VERSION 5.7 ;
  NOWIREEXTENSIONATPIN ON ;
  DIVIDERCHAR "/" ;
  BUSBITCHARS "[]" ;
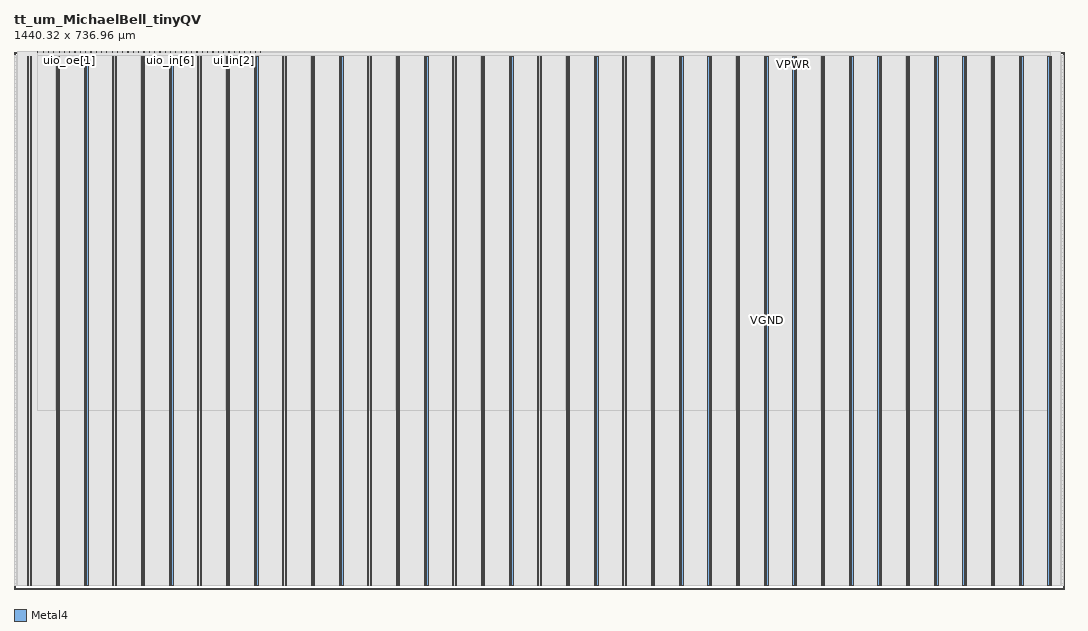
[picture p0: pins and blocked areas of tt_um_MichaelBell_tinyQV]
MACRO tt_um_MichaelBell_tinyQV
  CLASS BLOCK ;
  FOREIGN tt_um_MichaelBell_tinyQV ;
  ORIGIN 0.000 0.000 ;
  SIZE 1440.320 BY 736.960 ;
  PIN VGND
    DIRECTION INOUT ;
    USE GROUND ;
    PORT
      LAYER Metal4 ;
        RECT 22.180 4.740 23.780 731.100 ;
    END
    PORT
      LAYER Metal4 ;
        RECT 61.050 4.740 62.650 731.100 ;
    END
    PORT
      LAYER Metal4 ;
        RECT 99.920 4.740 101.520 731.100 ;
    END
    PORT
      LAYER Metal4 ;
        RECT 138.790 4.740 140.390 731.100 ;
    END
    PORT
      LAYER Metal4 ;
        RECT 177.660 4.740 179.260 731.100 ;
    END
    PORT
      LAYER Metal4 ;
        RECT 216.530 4.740 218.130 731.100 ;
    END
    PORT
      LAYER Metal4 ;
        RECT 255.400 4.740 257.000 731.100 ;
    END
    PORT
      LAYER Metal4 ;
        RECT 294.270 4.740 295.870 731.100 ;
    END
    PORT
      LAYER Metal4 ;
        RECT 333.140 4.740 334.740 731.100 ;
    END
    PORT
      LAYER Metal4 ;
        RECT 372.010 4.740 373.610 731.100 ;
    END
    PORT
      LAYER Metal4 ;
        RECT 410.880 4.740 412.480 731.100 ;
    END
    PORT
      LAYER Metal4 ;
        RECT 449.750 4.740 451.350 731.100 ;
    END
    PORT
      LAYER Metal4 ;
        RECT 488.620 4.740 490.220 731.100 ;
    END
    PORT
      LAYER Metal4 ;
        RECT 527.490 4.740 529.090 731.100 ;
    END
    PORT
      LAYER Metal4 ;
        RECT 566.360 4.740 567.960 731.100 ;
    END
    PORT
      LAYER Metal4 ;
        RECT 605.230 4.740 606.830 731.100 ;
    END
    PORT
      LAYER Metal4 ;
        RECT 644.100 4.740 645.700 731.100 ;
    END
    PORT
      LAYER Metal4 ;
        RECT 682.970 4.740 684.570 731.100 ;
    END
    PORT
      LAYER Metal4 ;
        RECT 721.840 4.740 723.440 731.100 ;
    END
    PORT
      LAYER Metal4 ;
        RECT 760.710 4.740 762.310 731.100 ;
    END
    PORT
      LAYER Metal4 ;
        RECT 799.580 4.740 801.180 731.100 ;
    END
    PORT
      LAYER Metal4 ;
        RECT 838.450 4.740 840.050 731.100 ;
    END
    PORT
      LAYER Metal4 ;
        RECT 877.320 4.740 878.920 731.100 ;
    END
    PORT
      LAYER Metal4 ;
        RECT 916.190 4.740 917.790 731.100 ;
    END
    PORT
      LAYER Metal4 ;
        RECT 955.060 4.740 956.660 731.100 ;
    END
    PORT
      LAYER Metal4 ;
        RECT 993.930 4.740 995.530 731.100 ;
    END
    PORT
      LAYER Metal4 ;
        RECT 1032.800 4.740 1034.400 731.100 ;
    END
    PORT
      LAYER Metal4 ;
        RECT 1071.670 4.740 1073.270 731.100 ;
    END
    PORT
      LAYER Metal4 ;
        RECT 1110.540 4.740 1112.140 731.100 ;
    END
    PORT
      LAYER Metal4 ;
        RECT 1149.410 4.740 1151.010 731.100 ;
    END
    PORT
      LAYER Metal4 ;
        RECT 1188.280 4.740 1189.880 731.100 ;
    END
    PORT
      LAYER Metal4 ;
        RECT 1227.150 4.740 1228.750 731.100 ;
    END
    PORT
      LAYER Metal4 ;
        RECT 1266.020 4.740 1267.620 731.100 ;
    END
    PORT
      LAYER Metal4 ;
        RECT 1304.890 4.740 1306.490 731.100 ;
    END
    PORT
      LAYER Metal4 ;
        RECT 1343.760 4.740 1345.360 731.100 ;
    END
    PORT
      LAYER Metal4 ;
        RECT 1382.630 4.740 1384.230 731.100 ;
    END
    PORT
      LAYER Metal4 ;
        RECT 1421.500 4.740 1423.100 731.100 ;
    END
  END VGND
  PIN VPWR
    DIRECTION INOUT ;
    USE POWER ;
    PORT
      LAYER Metal4 ;
        RECT 18.880 4.740 20.480 731.100 ;
    END
    PORT
      LAYER Metal4 ;
        RECT 57.750 4.740 59.350 731.100 ;
    END
    PORT
      LAYER Metal4 ;
        RECT 96.620 4.740 98.220 731.100 ;
    END
    PORT
      LAYER Metal4 ;
        RECT 135.490 4.740 137.090 731.100 ;
    END
    PORT
      LAYER Metal4 ;
        RECT 174.360 4.740 175.960 731.100 ;
    END
    PORT
      LAYER Metal4 ;
        RECT 213.230 4.740 214.830 731.100 ;
    END
    PORT
      LAYER Metal4 ;
        RECT 252.100 4.740 253.700 731.100 ;
    END
    PORT
      LAYER Metal4 ;
        RECT 290.970 4.740 292.570 731.100 ;
    END
    PORT
      LAYER Metal4 ;
        RECT 329.840 4.740 331.440 731.100 ;
    END
    PORT
      LAYER Metal4 ;
        RECT 368.710 4.740 370.310 731.100 ;
    END
    PORT
      LAYER Metal4 ;
        RECT 407.580 4.740 409.180 731.100 ;
    END
    PORT
      LAYER Metal4 ;
        RECT 446.450 4.740 448.050 731.100 ;
    END
    PORT
      LAYER Metal4 ;
        RECT 485.320 4.740 486.920 731.100 ;
    END
    PORT
      LAYER Metal4 ;
        RECT 524.190 4.740 525.790 731.100 ;
    END
    PORT
      LAYER Metal4 ;
        RECT 563.060 4.740 564.660 731.100 ;
    END
    PORT
      LAYER Metal4 ;
        RECT 601.930 4.740 603.530 731.100 ;
    END
    PORT
      LAYER Metal4 ;
        RECT 640.800 4.740 642.400 731.100 ;
    END
    PORT
      LAYER Metal4 ;
        RECT 679.670 4.740 681.270 731.100 ;
    END
    PORT
      LAYER Metal4 ;
        RECT 718.540 4.740 720.140 731.100 ;
    END
    PORT
      LAYER Metal4 ;
        RECT 757.410 4.740 759.010 731.100 ;
    END
    PORT
      LAYER Metal4 ;
        RECT 796.280 4.740 797.880 731.100 ;
    END
    PORT
      LAYER Metal4 ;
        RECT 835.150 4.740 836.750 731.100 ;
    END
    PORT
      LAYER Metal4 ;
        RECT 874.020 4.740 875.620 731.100 ;
    END
    PORT
      LAYER Metal4 ;
        RECT 912.890 4.740 914.490 731.100 ;
    END
    PORT
      LAYER Metal4 ;
        RECT 951.760 4.740 953.360 731.100 ;
    END
    PORT
      LAYER Metal4 ;
        RECT 990.630 4.740 992.230 731.100 ;
    END
    PORT
      LAYER Metal4 ;
        RECT 1029.500 4.740 1031.100 731.100 ;
    END
    PORT
      LAYER Metal4 ;
        RECT 1068.370 4.740 1069.970 731.100 ;
    END
    PORT
      LAYER Metal4 ;
        RECT 1107.240 4.740 1108.840 731.100 ;
    END
    PORT
      LAYER Metal4 ;
        RECT 1146.110 4.740 1147.710 731.100 ;
    END
    PORT
      LAYER Metal4 ;
        RECT 1184.980 4.740 1186.580 731.100 ;
    END
    PORT
      LAYER Metal4 ;
        RECT 1223.850 4.740 1225.450 731.100 ;
    END
    PORT
      LAYER Metal4 ;
        RECT 1262.720 4.740 1264.320 731.100 ;
    END
    PORT
      LAYER Metal4 ;
        RECT 1301.590 4.740 1303.190 731.100 ;
    END
    PORT
      LAYER Metal4 ;
        RECT 1340.460 4.740 1342.060 731.100 ;
    END
    PORT
      LAYER Metal4 ;
        RECT 1379.330 4.740 1380.930 731.100 ;
    END
    PORT
      LAYER Metal4 ;
        RECT 1418.200 4.740 1419.800 731.100 ;
    END
  END VPWR
  PIN clk
    DIRECTION INPUT ;
    USE SIGNAL ;
    ANTENNAGATEAREA 10.823999 ;
    PORT
      LAYER Metal4 ;
        RECT 331.090 735.960 331.390 736.960 ;
    END
  END clk
  PIN ena
    DIRECTION INPUT ;
    USE SIGNAL ;
    PORT
      LAYER Metal4 ;
        RECT 338.370 735.960 338.670 736.960 ;
    END
  END ena
  PIN rst_n
    DIRECTION INPUT ;
    USE SIGNAL ;
    ANTENNAGATEAREA 0.396000 ;
    PORT
      LAYER Metal4 ;
        RECT 323.810 735.960 324.110 736.960 ;
    END
  END rst_n
  PIN ui_in[0]
    DIRECTION INPUT ;
    USE SIGNAL ;
    ANTENNAGATEAREA 0.396000 ;
    PORT
      LAYER Metal4 ;
        RECT 316.530 735.960 316.830 736.960 ;
    END
  END ui_in[0]
  PIN ui_in[1]
    DIRECTION INPUT ;
    USE SIGNAL ;
    ANTENNAGATEAREA 0.396000 ;
    PORT
      LAYER Metal4 ;
        RECT 309.250 735.960 309.550 736.960 ;
    END
  END ui_in[1]
  PIN ui_in[2]
    DIRECTION INPUT ;
    USE SIGNAL ;
    ANTENNAGATEAREA 0.396000 ;
    PORT
      LAYER Metal4 ;
        RECT 301.970 735.960 302.270 736.960 ;
    END
  END ui_in[2]
  PIN ui_in[3]
    DIRECTION INPUT ;
    USE SIGNAL ;
    ANTENNAGATEAREA 0.396000 ;
    PORT
      LAYER Metal4 ;
        RECT 294.690 735.960 294.990 736.960 ;
    END
  END ui_in[3]
  PIN ui_in[4]
    DIRECTION INPUT ;
    USE SIGNAL ;
    ANTENNAGATEAREA 0.396000 ;
    PORT
      LAYER Metal4 ;
        RECT 287.410 735.960 287.710 736.960 ;
    END
  END ui_in[4]
  PIN ui_in[5]
    DIRECTION INPUT ;
    USE SIGNAL ;
    ANTENNAGATEAREA 0.396000 ;
    PORT
      LAYER Metal4 ;
        RECT 280.130 735.960 280.430 736.960 ;
    END
  END ui_in[5]
  PIN ui_in[6]
    DIRECTION INPUT ;
    USE SIGNAL ;
    ANTENNAGATEAREA 0.396000 ;
    PORT
      LAYER Metal4 ;
        RECT 272.850 735.960 273.150 736.960 ;
    END
  END ui_in[6]
  PIN ui_in[7]
    DIRECTION INPUT ;
    USE SIGNAL ;
    ANTENNAGATEAREA 0.396000 ;
    PORT
      LAYER Metal4 ;
        RECT 265.570 735.960 265.870 736.960 ;
    END
  END ui_in[7]
  PIN uio_in[0]
    DIRECTION INPUT ;
    USE SIGNAL ;
    PORT
      LAYER Metal4 ;
        RECT 258.290 735.960 258.590 736.960 ;
    END
  END uio_in[0]
  PIN uio_in[1]
    DIRECTION INPUT ;
    USE SIGNAL ;
    ANTENNAGATEAREA 0.396000 ;
    PORT
      LAYER Metal4 ;
        RECT 251.010 735.960 251.310 736.960 ;
    END
  END uio_in[1]
  PIN uio_in[2]
    DIRECTION INPUT ;
    USE SIGNAL ;
    ANTENNAGATEAREA 0.396000 ;
    PORT
      LAYER Metal4 ;
        RECT 243.730 735.960 244.030 736.960 ;
    END
  END uio_in[2]
  PIN uio_in[3]
    DIRECTION INPUT ;
    USE SIGNAL ;
    PORT
      LAYER Metal4 ;
        RECT 236.450 735.960 236.750 736.960 ;
    END
  END uio_in[3]
  PIN uio_in[4]
    DIRECTION INPUT ;
    USE SIGNAL ;
    ANTENNAGATEAREA 0.396000 ;
    PORT
      LAYER Metal4 ;
        RECT 229.170 735.960 229.470 736.960 ;
    END
  END uio_in[4]
  PIN uio_in[5]
    DIRECTION INPUT ;
    USE SIGNAL ;
    ANTENNAGATEAREA 0.396000 ;
    PORT
      LAYER Metal4 ;
        RECT 221.890 735.960 222.190 736.960 ;
    END
  END uio_in[5]
  PIN uio_in[6]
    DIRECTION INPUT ;
    USE SIGNAL ;
    PORT
      LAYER Metal4 ;
        RECT 214.610 735.960 214.910 736.960 ;
    END
  END uio_in[6]
  PIN uio_in[7]
    DIRECTION INPUT ;
    USE SIGNAL ;
    PORT
      LAYER Metal4 ;
        RECT 207.330 735.960 207.630 736.960 ;
    END
  END uio_in[7]
  PIN uio_oe[0]
    DIRECTION OUTPUT ;
    USE SIGNAL ;
    ANTENNADIFFAREA 1.386000 ;
    PORT
      LAYER Metal4 ;
        RECT 83.570 735.960 83.870 736.960 ;
    END
  END uio_oe[0]
  PIN uio_oe[1]
    DIRECTION OUTPUT ;
    USE SIGNAL ;
    ANTENNADIFFAREA 1.386000 ;
    PORT
      LAYER Metal4 ;
        RECT 76.290 735.960 76.590 736.960 ;
    END
  END uio_oe[1]
  PIN uio_oe[2]
    DIRECTION OUTPUT ;
    USE SIGNAL ;
    ANTENNADIFFAREA 1.386000 ;
    PORT
      LAYER Metal4 ;
        RECT 69.010 735.960 69.310 736.960 ;
    END
  END uio_oe[2]
  PIN uio_oe[3]
    DIRECTION OUTPUT ;
    USE SIGNAL ;
    ANTENNADIFFAREA 1.386000 ;
    PORT
      LAYER Metal4 ;
        RECT 61.730 735.960 62.030 736.960 ;
    END
  END uio_oe[3]
  PIN uio_oe[4]
    DIRECTION OUTPUT ;
    USE SIGNAL ;
    ANTENNADIFFAREA 1.386000 ;
    PORT
      LAYER Metal4 ;
        RECT 54.450 735.960 54.750 736.960 ;
    END
  END uio_oe[4]
  PIN uio_oe[5]
    DIRECTION OUTPUT ;
    USE SIGNAL ;
    ANTENNAGATEAREA 1.707000 ;
    ANTENNADIFFAREA 1.386000 ;
    PORT
      LAYER Metal4 ;
        RECT 47.170 735.960 47.470 736.960 ;
    END
  END uio_oe[5]
  PIN uio_oe[6]
    DIRECTION OUTPUT ;
    USE SIGNAL ;
    ANTENNADIFFAREA 1.386000 ;
    PORT
      LAYER Metal4 ;
        RECT 39.890 735.960 40.190 736.960 ;
    END
  END uio_oe[6]
  PIN uio_oe[7]
    DIRECTION OUTPUT ;
    USE SIGNAL ;
    ANTENNADIFFAREA 1.386000 ;
    PORT
      LAYER Metal4 ;
        RECT 32.610 735.960 32.910 736.960 ;
    END
  END uio_oe[7]
  PIN uio_out[0]
    DIRECTION OUTPUT ;
    USE SIGNAL ;
    ANTENNADIFFAREA 1.386000 ;
    PORT
      LAYER Metal4 ;
        RECT 141.810 735.960 142.110 736.960 ;
    END
  END uio_out[0]
  PIN uio_out[1]
    DIRECTION OUTPUT ;
    USE SIGNAL ;
    ANTENNADIFFAREA 1.126400 ;
    PORT
      LAYER Metal4 ;
        RECT 134.530 735.960 134.830 736.960 ;
    END
  END uio_out[1]
  PIN uio_out[2]
    DIRECTION OUTPUT ;
    USE SIGNAL ;
    ANTENNADIFFAREA 1.126400 ;
    PORT
      LAYER Metal4 ;
        RECT 127.250 735.960 127.550 736.960 ;
    END
  END uio_out[2]
  PIN uio_out[3]
    DIRECTION OUTPUT ;
    USE SIGNAL ;
    ANTENNADIFFAREA 1.386000 ;
    PORT
      LAYER Metal4 ;
        RECT 119.970 735.960 120.270 736.960 ;
    END
  END uio_out[3]
  PIN uio_out[4]
    DIRECTION OUTPUT ;
    USE SIGNAL ;
    ANTENNADIFFAREA 3.287600 ;
    PORT
      LAYER Metal4 ;
        RECT 112.690 735.960 112.990 736.960 ;
    END
  END uio_out[4]
  PIN uio_out[5]
    DIRECTION OUTPUT ;
    USE SIGNAL ;
    ANTENNADIFFAREA 1.126400 ;
    PORT
      LAYER Metal4 ;
        RECT 105.410 735.960 105.710 736.960 ;
    END
  END uio_out[5]
  PIN uio_out[6]
    DIRECTION OUTPUT ;
    USE SIGNAL ;
    ANTENNADIFFAREA 1.386000 ;
    PORT
      LAYER Metal4 ;
        RECT 98.130 735.960 98.430 736.960 ;
    END
  END uio_out[6]
  PIN uio_out[7]
    DIRECTION OUTPUT ;
    USE SIGNAL ;
    ANTENNADIFFAREA 1.386000 ;
    PORT
      LAYER Metal4 ;
        RECT 90.850 735.960 91.150 736.960 ;
    END
  END uio_out[7]
  PIN uo_out[0]
    DIRECTION OUTPUT ;
    USE SIGNAL ;
    ANTENNADIFFAREA 3.733500 ;
    PORT
      LAYER Metal4 ;
        RECT 200.050 735.960 200.350 736.960 ;
    END
  END uo_out[0]
  PIN uo_out[1]
    DIRECTION OUTPUT ;
    USE SIGNAL ;
    ANTENNADIFFAREA 3.362800 ;
    PORT
      LAYER Metal4 ;
        RECT 192.770 735.960 193.070 736.960 ;
    END
  END uo_out[1]
  PIN uo_out[2]
    DIRECTION OUTPUT ;
    USE SIGNAL ;
    ANTENNADIFFAREA 1.386000 ;
    PORT
      LAYER Metal4 ;
        RECT 185.490 735.960 185.790 736.960 ;
    END
  END uo_out[2]
  PIN uo_out[3]
    DIRECTION OUTPUT ;
    USE SIGNAL ;
    ANTENNADIFFAREA 1.386000 ;
    PORT
      LAYER Metal4 ;
        RECT 178.210 735.960 178.510 736.960 ;
    END
  END uo_out[3]
  PIN uo_out[4]
    DIRECTION OUTPUT ;
    USE SIGNAL ;
    ANTENNADIFFAREA 1.386000 ;
    PORT
      LAYER Metal4 ;
        RECT 170.930 735.960 171.230 736.960 ;
    END
  END uo_out[4]
  PIN uo_out[5]
    DIRECTION OUTPUT ;
    USE SIGNAL ;
    ANTENNADIFFAREA 1.386000 ;
    PORT
      LAYER Metal4 ;
        RECT 163.650 735.960 163.950 736.960 ;
    END
  END uo_out[5]
  PIN uo_out[6]
    DIRECTION OUTPUT ;
    USE SIGNAL ;
    ANTENNADIFFAREA 1.915500 ;
    PORT
      LAYER Metal4 ;
        RECT 156.370 735.960 156.670 736.960 ;
    END
  END uo_out[6]
  PIN uo_out[7]
    DIRECTION OUTPUT ;
    USE SIGNAL ;
    ANTENNADIFFAREA 3.362800 ;
    PORT
      LAYER Metal4 ;
        RECT 149.090 735.960 149.390 736.960 ;
    END
  END uo_out[7]
  OBS
      LAYER Pwell ;
        RECT 0.430 728.535 1439.890 731.230 ;
      LAYER Nwell ;
        RECT 0.430 722.985 1439.890 728.535 ;
      LAYER Pwell ;
        RECT 0.430 718.455 1439.890 722.985 ;
      LAYER Nwell ;
        RECT 0.430 712.905 1439.890 718.455 ;
      LAYER Pwell ;
        RECT 0.430 708.375 1439.890 712.905 ;
      LAYER Nwell ;
        RECT 0.430 702.825 1439.890 708.375 ;
      LAYER Pwell ;
        RECT 0.430 698.295 1439.890 702.825 ;
      LAYER Nwell ;
        RECT 0.430 692.745 1439.890 698.295 ;
      LAYER Pwell ;
        RECT 0.430 688.215 1439.890 692.745 ;
      LAYER Nwell ;
        RECT 0.430 682.665 1439.890 688.215 ;
      LAYER Pwell ;
        RECT 0.430 678.135 1439.890 682.665 ;
      LAYER Nwell ;
        RECT 0.430 672.585 1439.890 678.135 ;
      LAYER Pwell ;
        RECT 0.430 668.055 1439.890 672.585 ;
      LAYER Nwell ;
        RECT 0.430 662.505 1439.890 668.055 ;
      LAYER Pwell ;
        RECT 0.430 657.975 1439.890 662.505 ;
      LAYER Nwell ;
        RECT 0.430 652.425 1439.890 657.975 ;
      LAYER Pwell ;
        RECT 0.430 647.895 1439.890 652.425 ;
      LAYER Nwell ;
        RECT 0.430 642.345 1439.890 647.895 ;
      LAYER Pwell ;
        RECT 0.430 637.815 1439.890 642.345 ;
      LAYER Nwell ;
        RECT 0.430 632.265 1439.890 637.815 ;
      LAYER Pwell ;
        RECT 0.430 627.735 1439.890 632.265 ;
      LAYER Nwell ;
        RECT 0.430 622.185 1439.890 627.735 ;
      LAYER Pwell ;
        RECT 0.430 617.655 1439.890 622.185 ;
      LAYER Nwell ;
        RECT 0.430 612.105 1439.890 617.655 ;
      LAYER Pwell ;
        RECT 0.430 607.575 1439.890 612.105 ;
      LAYER Nwell ;
        RECT 0.430 602.025 1439.890 607.575 ;
      LAYER Pwell ;
        RECT 0.430 597.495 1439.890 602.025 ;
      LAYER Nwell ;
        RECT 0.430 591.945 1439.890 597.495 ;
      LAYER Pwell ;
        RECT 0.430 587.415 1439.890 591.945 ;
      LAYER Nwell ;
        RECT 0.430 581.865 1439.890 587.415 ;
      LAYER Pwell ;
        RECT 0.430 577.335 1439.890 581.865 ;
      LAYER Nwell ;
        RECT 0.430 571.785 1439.890 577.335 ;
      LAYER Pwell ;
        RECT 0.430 567.255 1439.890 571.785 ;
      LAYER Nwell ;
        RECT 0.430 561.705 1439.890 567.255 ;
      LAYER Pwell ;
        RECT 0.430 557.175 1439.890 561.705 ;
      LAYER Nwell ;
        RECT 0.430 551.625 1439.890 557.175 ;
      LAYER Pwell ;
        RECT 0.430 547.095 1439.890 551.625 ;
      LAYER Nwell ;
        RECT 0.430 541.545 1439.890 547.095 ;
      LAYER Pwell ;
        RECT 0.430 537.015 1439.890 541.545 ;
      LAYER Nwell ;
        RECT 0.430 531.465 1439.890 537.015 ;
      LAYER Pwell ;
        RECT 0.430 526.935 1439.890 531.465 ;
      LAYER Nwell ;
        RECT 0.430 521.385 1439.890 526.935 ;
      LAYER Pwell ;
        RECT 0.430 516.855 1439.890 521.385 ;
      LAYER Nwell ;
        RECT 0.430 511.305 1439.890 516.855 ;
      LAYER Pwell ;
        RECT 0.430 506.775 1439.890 511.305 ;
      LAYER Nwell ;
        RECT 0.430 501.225 1439.890 506.775 ;
      LAYER Pwell ;
        RECT 0.430 496.695 1439.890 501.225 ;
      LAYER Nwell ;
        RECT 0.430 491.145 1439.890 496.695 ;
      LAYER Pwell ;
        RECT 0.430 486.615 1439.890 491.145 ;
      LAYER Nwell ;
        RECT 0.430 481.065 1439.890 486.615 ;
      LAYER Pwell ;
        RECT 0.430 476.535 1439.890 481.065 ;
      LAYER Nwell ;
        RECT 0.430 470.985 1439.890 476.535 ;
      LAYER Pwell ;
        RECT 0.430 466.455 1439.890 470.985 ;
      LAYER Nwell ;
        RECT 0.430 460.905 1439.890 466.455 ;
      LAYER Pwell ;
        RECT 0.430 456.375 1439.890 460.905 ;
      LAYER Nwell ;
        RECT 0.430 450.825 1439.890 456.375 ;
      LAYER Pwell ;
        RECT 0.430 446.295 1439.890 450.825 ;
      LAYER Nwell ;
        RECT 0.430 440.745 1439.890 446.295 ;
      LAYER Pwell ;
        RECT 0.430 436.215 1439.890 440.745 ;
      LAYER Nwell ;
        RECT 0.430 430.665 1439.890 436.215 ;
      LAYER Pwell ;
        RECT 0.430 426.135 1439.890 430.665 ;
      LAYER Nwell ;
        RECT 0.430 420.585 1439.890 426.135 ;
      LAYER Pwell ;
        RECT 0.430 416.055 1439.890 420.585 ;
      LAYER Nwell ;
        RECT 0.430 410.505 1439.890 416.055 ;
      LAYER Pwell ;
        RECT 0.430 405.975 1439.890 410.505 ;
      LAYER Nwell ;
        RECT 0.430 400.425 1439.890 405.975 ;
      LAYER Pwell ;
        RECT 0.430 395.895 1439.890 400.425 ;
      LAYER Nwell ;
        RECT 0.430 390.345 1439.890 395.895 ;
      LAYER Pwell ;
        RECT 0.430 385.815 1439.890 390.345 ;
      LAYER Nwell ;
        RECT 0.430 380.265 1439.890 385.815 ;
      LAYER Pwell ;
        RECT 0.430 375.735 1439.890 380.265 ;
      LAYER Nwell ;
        RECT 0.430 370.185 1439.890 375.735 ;
      LAYER Pwell ;
        RECT 0.430 365.655 1439.890 370.185 ;
      LAYER Nwell ;
        RECT 0.430 360.105 1439.890 365.655 ;
      LAYER Pwell ;
        RECT 0.430 355.575 1439.890 360.105 ;
      LAYER Nwell ;
        RECT 0.430 350.025 1439.890 355.575 ;
      LAYER Pwell ;
        RECT 0.430 345.495 1439.890 350.025 ;
      LAYER Nwell ;
        RECT 0.430 339.945 1439.890 345.495 ;
      LAYER Pwell ;
        RECT 0.430 335.415 1439.890 339.945 ;
      LAYER Nwell ;
        RECT 0.430 329.865 1439.890 335.415 ;
      LAYER Pwell ;
        RECT 0.430 325.335 1439.890 329.865 ;
      LAYER Nwell ;
        RECT 0.430 319.785 1439.890 325.335 ;
      LAYER Pwell ;
        RECT 0.430 315.255 1439.890 319.785 ;
      LAYER Nwell ;
        RECT 0.430 309.705 1439.890 315.255 ;
      LAYER Pwell ;
        RECT 0.430 305.175 1439.890 309.705 ;
      LAYER Nwell ;
        RECT 0.430 299.625 1439.890 305.175 ;
      LAYER Pwell ;
        RECT 0.430 295.095 1439.890 299.625 ;
      LAYER Nwell ;
        RECT 0.430 289.545 1439.890 295.095 ;
      LAYER Pwell ;
        RECT 0.430 285.015 1439.890 289.545 ;
      LAYER Nwell ;
        RECT 0.430 279.465 1439.890 285.015 ;
      LAYER Pwell ;
        RECT 0.430 274.935 1439.890 279.465 ;
      LAYER Nwell ;
        RECT 0.430 269.385 1439.890 274.935 ;
      LAYER Pwell ;
        RECT 0.430 264.855 1439.890 269.385 ;
      LAYER Nwell ;
        RECT 0.430 259.305 1439.890 264.855 ;
      LAYER Pwell ;
        RECT 0.430 254.775 1439.890 259.305 ;
      LAYER Nwell ;
        RECT 0.430 249.225 1439.890 254.775 ;
      LAYER Pwell ;
        RECT 0.430 244.695 1439.890 249.225 ;
      LAYER Nwell ;
        RECT 0.430 239.145 1439.890 244.695 ;
      LAYER Pwell ;
        RECT 0.430 234.615 1439.890 239.145 ;
      LAYER Nwell ;
        RECT 0.430 229.065 1439.890 234.615 ;
      LAYER Pwell ;
        RECT 0.430 224.535 1439.890 229.065 ;
      LAYER Nwell ;
        RECT 0.430 218.985 1439.890 224.535 ;
      LAYER Pwell ;
        RECT 0.430 214.455 1439.890 218.985 ;
      LAYER Nwell ;
        RECT 0.430 208.905 1439.890 214.455 ;
      LAYER Pwell ;
        RECT 0.430 204.375 1439.890 208.905 ;
      LAYER Nwell ;
        RECT 0.430 198.825 1439.890 204.375 ;
      LAYER Pwell ;
        RECT 0.430 194.295 1439.890 198.825 ;
      LAYER Nwell ;
        RECT 0.430 188.745 1439.890 194.295 ;
      LAYER Pwell ;
        RECT 0.430 184.215 1439.890 188.745 ;
      LAYER Nwell ;
        RECT 0.430 178.665 1439.890 184.215 ;
      LAYER Pwell ;
        RECT 0.430 174.135 1439.890 178.665 ;
      LAYER Nwell ;
        RECT 0.430 168.585 1439.890 174.135 ;
      LAYER Pwell ;
        RECT 0.430 164.055 1439.890 168.585 ;
      LAYER Nwell ;
        RECT 0.430 158.505 1439.890 164.055 ;
      LAYER Pwell ;
        RECT 0.430 153.975 1439.890 158.505 ;
      LAYER Nwell ;
        RECT 0.430 148.425 1439.890 153.975 ;
      LAYER Pwell ;
        RECT 0.430 143.895 1439.890 148.425 ;
      LAYER Nwell ;
        RECT 0.430 138.345 1439.890 143.895 ;
      LAYER Pwell ;
        RECT 0.430 133.815 1439.890 138.345 ;
      LAYER Nwell ;
        RECT 0.430 128.265 1439.890 133.815 ;
      LAYER Pwell ;
        RECT 0.430 123.735 1439.890 128.265 ;
      LAYER Nwell ;
        RECT 0.430 118.185 1439.890 123.735 ;
      LAYER Pwell ;
        RECT 0.430 113.655 1439.890 118.185 ;
      LAYER Nwell ;
        RECT 0.430 108.105 1439.890 113.655 ;
      LAYER Pwell ;
        RECT 0.430 103.575 1439.890 108.105 ;
      LAYER Nwell ;
        RECT 0.430 98.025 1439.890 103.575 ;
      LAYER Pwell ;
        RECT 0.430 93.495 1439.890 98.025 ;
      LAYER Nwell ;
        RECT 0.430 87.945 1439.890 93.495 ;
      LAYER Pwell ;
        RECT 0.430 83.415 1439.890 87.945 ;
      LAYER Nwell ;
        RECT 0.430 77.865 1439.890 83.415 ;
      LAYER Pwell ;
        RECT 0.430 73.335 1439.890 77.865 ;
      LAYER Nwell ;
        RECT 0.430 67.785 1439.890 73.335 ;
      LAYER Pwell ;
        RECT 0.430 63.255 1439.890 67.785 ;
      LAYER Nwell ;
        RECT 0.430 57.705 1439.890 63.255 ;
      LAYER Pwell ;
        RECT 0.430 53.175 1439.890 57.705 ;
      LAYER Nwell ;
        RECT 0.430 47.625 1439.890 53.175 ;
      LAYER Pwell ;
        RECT 0.430 43.095 1439.890 47.625 ;
      LAYER Nwell ;
        RECT 0.430 37.545 1439.890 43.095 ;
      LAYER Pwell ;
        RECT 0.430 33.015 1439.890 37.545 ;
      LAYER Nwell ;
        RECT 0.430 27.465 1439.890 33.015 ;
      LAYER Pwell ;
        RECT 0.430 22.935 1439.890 27.465 ;
      LAYER Nwell ;
        RECT 0.430 17.385 1439.890 22.935 ;
      LAYER Pwell ;
        RECT 0.430 12.855 1439.890 17.385 ;
      LAYER Nwell ;
        RECT 0.430 7.305 1439.890 12.855 ;
      LAYER Pwell ;
        RECT 0.430 4.610 1439.890 7.305 ;
      LAYER Metal1 ;
        RECT 3.360 4.590 1436.960 731.250 ;
      LAYER Metal2 ;
        RECT 5.180 4.850 1435.140 736.870 ;
      LAYER Metal3 ;
        RECT 5.130 4.900 1435.190 736.820 ;
      LAYER Metal4 ;
        RECT 33.210 735.660 39.590 735.960 ;
        RECT 40.490 735.660 46.870 735.960 ;
        RECT 47.770 735.660 54.150 735.960 ;
        RECT 55.050 735.660 61.430 735.960 ;
        RECT 62.330 735.660 68.710 735.960 ;
        RECT 69.610 735.660 75.990 735.960 ;
        RECT 76.890 735.660 83.270 735.960 ;
        RECT 84.170 735.660 90.550 735.960 ;
        RECT 91.450 735.660 97.830 735.960 ;
        RECT 98.730 735.660 105.110 735.960 ;
        RECT 106.010 735.660 112.390 735.960 ;
        RECT 113.290 735.660 119.670 735.960 ;
        RECT 120.570 735.660 126.950 735.960 ;
        RECT 127.850 735.660 134.230 735.960 ;
        RECT 135.130 735.660 141.510 735.960 ;
        RECT 142.410 735.660 148.790 735.960 ;
        RECT 149.690 735.660 156.070 735.960 ;
        RECT 156.970 735.660 163.350 735.960 ;
        RECT 164.250 735.660 170.630 735.960 ;
        RECT 171.530 735.660 177.910 735.960 ;
        RECT 178.810 735.660 185.190 735.960 ;
        RECT 186.090 735.660 192.470 735.960 ;
        RECT 193.370 735.660 199.750 735.960 ;
        RECT 200.650 735.660 207.030 735.960 ;
        RECT 207.930 735.660 214.310 735.960 ;
        RECT 215.210 735.660 221.590 735.960 ;
        RECT 222.490 735.660 228.870 735.960 ;
        RECT 229.770 735.660 236.150 735.960 ;
        RECT 237.050 735.660 243.430 735.960 ;
        RECT 244.330 735.660 250.710 735.960 ;
        RECT 251.610 735.660 257.990 735.960 ;
        RECT 258.890 735.660 265.270 735.960 ;
        RECT 266.170 735.660 272.550 735.960 ;
        RECT 273.450 735.660 279.830 735.960 ;
        RECT 280.730 735.660 287.110 735.960 ;
        RECT 288.010 735.660 294.390 735.960 ;
        RECT 295.290 735.660 301.670 735.960 ;
        RECT 302.570 735.660 308.950 735.960 ;
        RECT 309.850 735.660 316.230 735.960 ;
        RECT 317.130 735.660 323.510 735.960 ;
        RECT 324.410 735.660 330.790 735.960 ;
        RECT 331.690 735.660 338.070 735.960 ;
        RECT 338.970 735.660 1421.140 735.960 ;
        RECT 32.620 731.400 1421.140 735.660 ;
        RECT 32.620 244.250 57.450 731.400 ;
        RECT 59.650 244.250 60.750 731.400 ;
        RECT 62.950 244.250 96.320 731.400 ;
        RECT 98.520 244.250 99.620 731.400 ;
        RECT 101.820 244.250 135.190 731.400 ;
        RECT 137.390 244.250 138.490 731.400 ;
        RECT 140.690 244.250 174.060 731.400 ;
        RECT 176.260 244.250 177.360 731.400 ;
        RECT 179.560 244.250 212.930 731.400 ;
        RECT 215.130 244.250 216.230 731.400 ;
        RECT 218.430 244.250 251.800 731.400 ;
        RECT 254.000 244.250 255.100 731.400 ;
        RECT 257.300 244.250 290.670 731.400 ;
        RECT 292.870 244.250 293.970 731.400 ;
        RECT 296.170 244.250 329.540 731.400 ;
        RECT 331.740 244.250 332.840 731.400 ;
        RECT 335.040 244.250 368.410 731.400 ;
        RECT 370.610 244.250 371.710 731.400 ;
        RECT 373.910 244.250 407.280 731.400 ;
        RECT 409.480 244.250 410.580 731.400 ;
        RECT 412.780 244.250 446.150 731.400 ;
        RECT 448.350 244.250 449.450 731.400 ;
        RECT 451.650 244.250 485.020 731.400 ;
        RECT 487.220 244.250 488.320 731.400 ;
        RECT 490.520 244.250 523.890 731.400 ;
        RECT 526.090 244.250 527.190 731.400 ;
        RECT 529.390 244.250 562.760 731.400 ;
        RECT 564.960 244.250 566.060 731.400 ;
        RECT 568.260 244.250 601.630 731.400 ;
        RECT 603.830 244.250 604.930 731.400 ;
        RECT 607.130 244.250 640.500 731.400 ;
        RECT 642.700 244.250 643.800 731.400 ;
        RECT 646.000 244.250 679.370 731.400 ;
        RECT 681.570 244.250 682.670 731.400 ;
        RECT 684.870 244.250 718.240 731.400 ;
        RECT 720.440 244.250 721.540 731.400 ;
        RECT 723.740 244.250 757.110 731.400 ;
        RECT 759.310 244.250 760.410 731.400 ;
        RECT 762.610 244.250 795.980 731.400 ;
        RECT 798.180 244.250 799.280 731.400 ;
        RECT 801.480 244.250 834.850 731.400 ;
        RECT 837.050 244.250 838.150 731.400 ;
        RECT 840.350 244.250 873.720 731.400 ;
        RECT 875.920 244.250 877.020 731.400 ;
        RECT 879.220 244.250 912.590 731.400 ;
        RECT 914.790 244.250 915.890 731.400 ;
        RECT 918.090 244.250 951.460 731.400 ;
        RECT 953.660 244.250 954.760 731.400 ;
        RECT 956.960 244.250 990.330 731.400 ;
        RECT 992.530 244.250 993.630 731.400 ;
        RECT 995.830 244.250 1029.200 731.400 ;
        RECT 1031.400 244.250 1032.500 731.400 ;
        RECT 1034.700 244.250 1068.070 731.400 ;
        RECT 1070.270 244.250 1071.370 731.400 ;
        RECT 1073.570 244.250 1106.940 731.400 ;
        RECT 1109.140 244.250 1110.240 731.400 ;
        RECT 1112.440 244.250 1145.810 731.400 ;
        RECT 1148.010 244.250 1149.110 731.400 ;
        RECT 1151.310 244.250 1184.680 731.400 ;
        RECT 1186.880 244.250 1187.980 731.400 ;
        RECT 1190.180 244.250 1223.550 731.400 ;
        RECT 1225.750 244.250 1226.850 731.400 ;
        RECT 1229.050 244.250 1262.420 731.400 ;
        RECT 1264.620 244.250 1265.720 731.400 ;
        RECT 1267.920 244.250 1301.290 731.400 ;
        RECT 1303.490 244.250 1304.590 731.400 ;
        RECT 1306.790 244.250 1340.160 731.400 ;
        RECT 1342.360 244.250 1343.460 731.400 ;
        RECT 1345.660 244.250 1379.030 731.400 ;
        RECT 1381.230 244.250 1382.330 731.400 ;
        RECT 1384.530 244.250 1417.900 731.400 ;
        RECT 1420.100 244.250 1421.140 731.400 ;
  END
END tt_um_MichaelBell_tinyQV
END LIBRARY

